VERSION 5.8 ;
BUSBITCHARS "[]" ;
DIVIDERCHAR "/" ;
CLEARANCEMEASURE EUCLIDEAN ;

SITE coresite_DH_P
    SIZE 0.0450 BY 0.2880 ;
    CLASS CORE ;
    SYMMETRY X Y ;
END coresite_DH_P

SITE coresite_DH_N
    SIZE 0.0450 BY 0.2880 ;
    CLASS CORE ;
    SYMMETRY X Y ;
END coresite_DH_N

SITE coresite
    SIZE 0.0450 BY 0.1440 ;
    CLASS CORE ;
    SYMMETRY X Y ;
END coresite

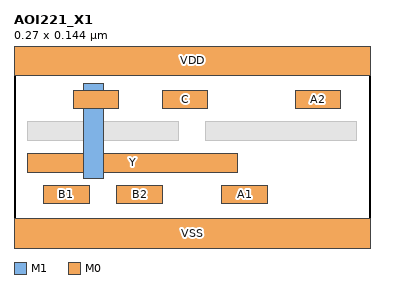
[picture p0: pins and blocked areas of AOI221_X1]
MACRO AOI221_X1
  CLASS CORE ;
  ORIGIN 0 0 ;
  FOREIGN AOI221_X1 0 0 ;
  SIZE 0.2700 BY 0.1440 ;
  SYMMETRY X Y ;
  SITE coresite ;
  PIN Y
    DIRECTION OUTPUT ;
    USE SIGNAL ;
    PORT
      LAYER M1 ;
        RECT 0.0525 0.1200 0.0675 0.0480 ;
      LAYER M0 ;
        RECT 0.0105 0.0670 0.1695 0.0530 ;
        RECT 0.0450 0.1150 0.0795 0.1010 ;
    END
  END Y
  PIN B1
    DIRECTION INPUT ;
    USE SIGNAL ;
    PORT
      LAYER M0 ;
        RECT 0.0225 0.0430 0.0570 0.0290 ;
    END
  END B1
  PIN B2
    DIRECTION INPUT ;
    USE SIGNAL ;
    PORT
      LAYER M0 ;
        RECT 0.0780 0.0430 0.1125 0.0290 ;
    END
  END B2
  PIN A1
    DIRECTION INPUT ;
    USE SIGNAL ;
    PORT
      LAYER M0 ;
        RECT 0.1575 0.0430 0.1920 0.0290 ;
    END
  END A1
  PIN C
    DIRECTION INPUT ;
    USE SIGNAL ;
    PORT
      LAYER M0 ;
        RECT 0.1125 0.1150 0.1470 0.1010 ;
    END
  END C
  PIN A2
    DIRECTION INPUT ;
    USE SIGNAL ;
    PORT
      LAYER M0 ;
        RECT 0.2130 0.1150 0.2475 0.1010 ;
    END
  END A2
  PIN VDD
    DIRECTION INOUT ;
    USE POWER ;
    SHAPE ABUTMENT ;
    PORT
      LAYER M0 ;
        RECT 0.0000 0.1260 0.2700 0.1620 ;
    END
  END VDD
  PIN VSS
    DIRECTION INOUT ;
    USE GROUND ;
    SHAPE ABUTMENT ;
    PORT
      LAYER M0 ;
        RECT 0.0000 -0.0180 0.2700 0.0180 ;
    END
  END VSS
  OBS
      LAYER V0 ;
        RECT 0.0530 0.1010 0.0670 0.1150 ;
        RECT 0.0530 0.0530 0.0670 0.0670 ;
      LAYER M0 ;
        RECT 0.0105 0.0770 0.1245 0.0910 ;
        RECT 0.1455 0.0770 0.2595 0.0910 ;
  END
END AOI221_X1

END LIBRARY
